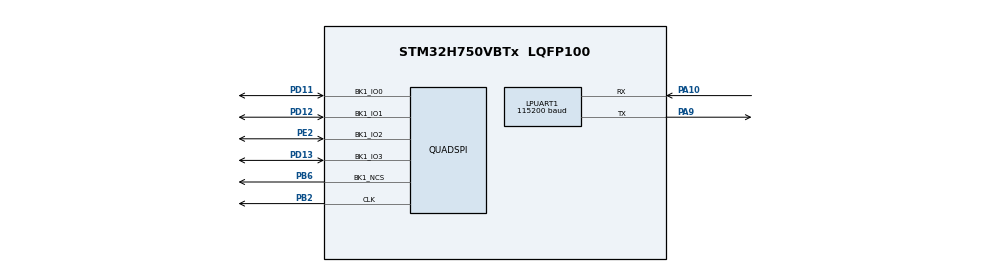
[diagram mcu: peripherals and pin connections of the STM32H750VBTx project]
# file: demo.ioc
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LPUART1.BaudRate=115200
Mcu.Family=STM32H7
Mcu.Name=STM32H750VBTx
Mcu.Package=LQFP100
NVIC.PriorityGroup=NVIC_PRIORITYGROUP_4
PA10.Mode=Asynchronous
PA10.Signal=LPUART1_RX
PA13\ (JTMS/SWDIO).Mode=Serial_Wire
PA13\ (JTMS/SWDIO).Signal=DEBUG_JTMS-SWDIO
PA14\ (JTCK/SWCLK).Mode=Serial_Wire
PA14\ (JTCK/SWCLK).Signal=DEBUG_JTCK-SWCLK
PA9.Mode=Asynchronous
PA9.Signal=LPUART1_TX
PB2.Mode=Single Bank 1
PB2.Signal=QUADSPI_CLK
PB6.Mode=Single Bank 1
PB6.Signal=QUADSPI_BK1_NCS
PC14-OSC32_IN\ (OSC32_IN).Mode=LSE-External-Oscillator
PC14-OSC32_IN\ (OSC32_IN).Signal=RCC_OSC32_IN
PC15-OSC32_OUT\ (OSC32_OUT).Mode=LSE-External-Oscillator
PC15-OSC32_OUT\ (OSC32_OUT).Signal=RCC_OSC32_OUT
PD11.Mode=Single Bank 1
PD11.Signal=QUADSPI_BK1_IO0
PD12.Mode=Single Bank 1
PD12.Signal=QUADSPI_BK1_IO1
PD13.Mode=Single Bank 1
PD13.Signal=QUADSPI_BK1_IO3
PE2.Mode=Single Bank 1
PE2.Signal=QUADSPI_BK1_IO2
PH0-OSC_IN\ (PH0).Mode=HSE-External-Oscillator
PH0-OSC_IN\ (PH0).Signal=RCC_OSC_IN
PH1-OSC_OUT\ (PH1).Mode=HSE-External-Oscillator
PH1-OSC_OUT\ (PH1).Signal=RCC_OSC_OUT
ProjectManager.HeapSize=0x200
ProjectManager.StackSize=0x400
ProjectManager.TargetToolchain=MDK-ARM V5.32
QUADSPI.ChipSelectHighTime=QSPI_CS_HIGH_TIME_2_CYCLE
QUADSPI.ClockPrescaler=1
QUADSPI.FifoThreshold=16
QUADSPI.FlashSize=22
QUADSPI.SampleShifting=QSPI_SAMPLE_SHIFTING_HALFCYCLE
RCC.ADCFreq_Value=75000000
RCC.APB1Freq_Value=100000000
RCC.APB2Freq_Value=100000000
RCC.APB3Freq_Value=100000000
RCC.APB4Freq_Value=100000000
RCC.CortexFreq_Value=400000000
RCC.D1PPRE=RCC_APB3_DIV2
RCC.D2PPRE1=RCC_APB1_DIV2
RCC.D2PPRE2=RCC_APB2_DIV2
RCC.D3PPRE=RCC_APB4_DIV2
RCC.DIVM1=2
RCC.DIVM2=2
RCC.DIVM3=2
RCC.DIVN1=64
RCC.DIVN2=12
RCC.DIVN3=24
RCC.DIVQ1=8
RCC.DIVR1=4
RCC.HCLKFreq_Value=200000000
RCC.HPRE=RCC_HCLK_DIV2
RCC.PLL2FRACN=0
RCC.PLL2_VCO_SEL-AdvancedSettings=RCC_PLL2VCOMEDIUM
RCC.PLL3FRACN=0
RCC.PLLFRACN=0
RCC.PLLSourceVirtual=RCC_PLLSOURCE_HSE
RCC.SYSCLKFreq_VALUE=400000000
RCC.SYSCLKSource=RCC_SYSCLKSOURCE_PLLCLK
RCC.USBFreq_Value=100000000
board=custom

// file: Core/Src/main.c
/* USER CODE BEGIN Header */
/**
  ******************************************************************************
  * @file           : main.c
  * @brief          : Main program body
  ******************************************************************************
  * @attention
  *
  * Copyright (c) 2023 STMicroelectronics.
  * All rights reserved.
  *
  * This software is licensed under terms that can be found in the LICENSE file
  * in the root directory of this software component.
  * If no LICENSE file comes with this software, it is provided AS-IS.
  *
  ******************************************************************************
  */
/* USER CODE END Header */
#include "main.h"
#include "usart.h"
#include "quadspi.h"
#include "gpio.h"

/* USER CODE BEGIN Includes */
#include <stdio.h>
#include <string.h>
#include <stdlib.h>
#include "QSPI_Flash.h"
/* USER CODE END Includes */

void SystemClock_Config(void);

int main(void)
{

  /* MCU Configuration--------------------------------------------------------*/

  /* Reset of all peripherals, Initializes the Flash interface and the Systick. */
  HAL_Init();

  /* Configure the system clock */
  SystemClock_Config();

  /* Initialize all configured peripherals */
  MX_GPIO_Init();
  MX_LPUART1_UART_Init();
  MX_QUADSPI_Init();
  /* USER CODE BEGIN 2 */
	printf("work\r\n");
  uint8_t data1[256] = {0};
  uint8_t data2[256] = {0};
  QSPI_InitFlash();
  printf("Completed!\r\n");
  printf("read JEDEC:%x\r\n",QSPI_ReadJEDEC());

  printf("Writing data:\r\n");
  for(int i = 0; i < sizeof(data1); i++){
    data1[i] = rand()%256;
    printf("0x%x  ", data1[i]);
    if(i%8 == 7){
      printf("\r\n");
    }
  }

  QSPI_EraseSector(0);
  QSPI_Write(data1, 0, sizeof(data1));
  printf("write over\r\n");

  HAL_Delay(1000);

  printf("Reading data:\r\n");
  QSPI_SetQuardEnable(true);
  printf("QuadRead:%d\r\n",QSPI_QuadOutputFastRead(data2, 0, sizeof(data2)));

  for(int i = 0; i < sizeof(data2); i++){
    printf("0X%x  ", data2[i]);
    if(i%8 == 7){
      printf("\r\n");
    }
  }
  printf("read over\r\n");

  /* USER CODE END 2 */

  /* Infinite loop */
  while (1)
  {

  }
}

void SystemClock_Config(void)
{
  RCC_OscInitTypeDef RCC_OscInitStruct = {0};
  RCC_ClkInitTypeDef RCC_ClkInitStruct = {0};

  /** Supply configuration update enable
  */
  HAL_PWREx_ConfigSupply(PWR_LDO_SUPPLY);

  /** Configure the main internal regulator output voltage
  */
  __HAL_PWR_VOLTAGESCALING_CONFIG(PWR_REGULATOR_VOLTAGE_SCALE3);

  while(!__HAL_PWR_GET_FLAG(PWR_FLAG_VOSRDY)) {}

  /** Initializes the RCC Oscillators according to the specified parameters
  * in the RCC_OscInitTypeDef structure.
  */
  RCC_OscInitStruct.OscillatorType = RCC_OSCILLATORTYPE_HSI;
  RCC_OscInitStruct.HSIState = RCC_HSI_DIV1;
  RCC_OscInitStruct.HSICalibrationValue = RCC_HSICALIBRATION_DEFAULT;
  RCC_OscInitStruct.PLL.PLLState = RCC_PLL_NONE;
  if (HAL_RCC_OscConfig(&RCC_OscInitStruct) != HAL_OK)
  {
    Error_Handler();
  }

  /** Initializes the CPU, AHB and APB buses clocks
  */
  RCC_ClkInitStruct.ClockType = RCC_CLOCKTYPE_HCLK|RCC_CLOCKTYPE_SYSCLK
                              |RCC_CLOCKTYPE_PCLK1|RCC_CLOCKTYPE_PCLK2
                              |RCC_CLOCKTYPE_D3PCLK1|RCC_CLOCKTYPE_D1PCLK1;
  RCC_ClkInitStruct.SYSCLKSource = RCC_SYSCLKSOURCE_HSI;
  RCC_ClkInitStruct.SYSCLKDivider = RCC_SYSCLK_DIV1;
  RCC_ClkInitStruct.AHBCLKDivider = RCC_HCLK_DIV1;
  RCC_ClkInitStruct.APB3CLKDivider = RCC_APB3_DIV2;
  RCC_ClkInitStruct.APB1CLKDivider = RCC_APB1_DIV2;
  RCC_ClkInitStruct.APB2CLKDivider = RCC_APB2_DIV2;
  RCC_ClkInitStruct.APB4CLKDivider = RCC_APB4_DIV2;

  if (HAL_RCC_ClockConfig(&RCC_ClkInitStruct, FLASH_LATENCY_1) != HAL_OK)
  {
    Error_Handler();
  }
}

void Error_Handler(void)
{
  __disable_irq();
  while (1)
  {
  }
}
